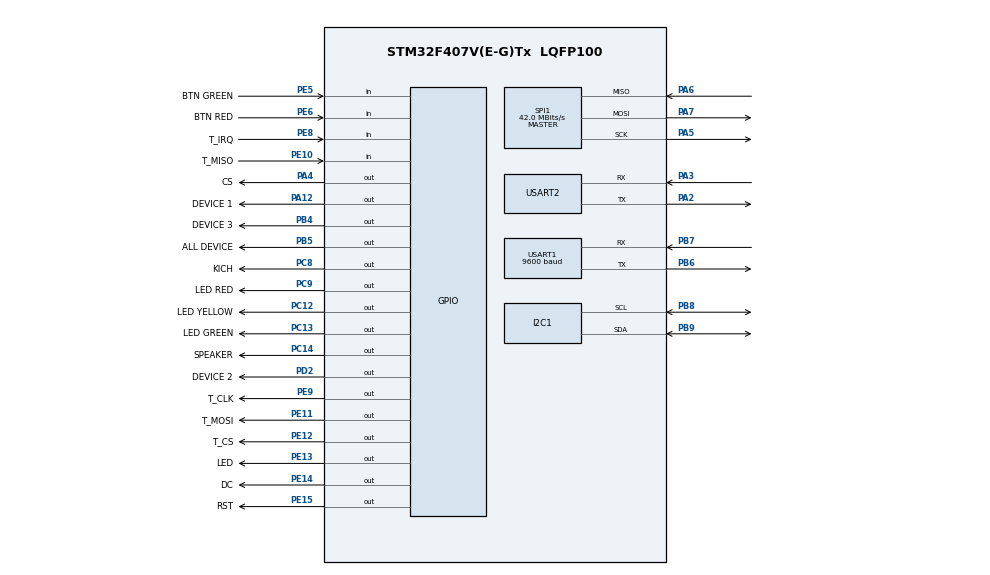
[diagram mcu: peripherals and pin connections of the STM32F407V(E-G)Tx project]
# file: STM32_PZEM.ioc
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Dma.Request0=USART1_RX
Dma.Request1=USART2_RX
Dma.Request2=USART2_TX
Dma.USART1_RX.0.Direction=DMA_PERIPH_TO_MEMORY
Dma.USART1_RX.0.FIFOMode=DMA_FIFOMODE_DISABLE
Dma.USART1_RX.0.Instance=DMA2_Stream2
Dma.USART1_RX.0.MemDataAlignment=DMA_MDATAALIGN_BYTE
Dma.USART1_RX.0.MemInc=DMA_MINC_ENABLE
Dma.USART1_RX.0.Mode=DMA_CIRCULAR
Dma.USART1_RX.0.PeriphDataAlignment=DMA_PDATAALIGN_BYTE
Dma.USART1_RX.0.PeriphInc=DMA_PINC_DISABLE
Dma.USART1_RX.0.Priority=DMA_PRIORITY_LOW
Dma.USART2_RX.1.Direction=DMA_PERIPH_TO_MEMORY
Dma.USART2_RX.1.FIFOMode=DMA_FIFOMODE_DISABLE
Dma.USART2_RX.1.Instance=DMA1_Stream5
Dma.USART2_RX.1.MemDataAlignment=DMA_MDATAALIGN_BYTE
Dma.USART2_RX.1.MemInc=DMA_MINC_ENABLE
Dma.USART2_RX.1.Mode=DMA_CIRCULAR
Dma.USART2_RX.1.PeriphDataAlignment=DMA_PDATAALIGN_BYTE
Dma.USART2_RX.1.PeriphInc=DMA_PINC_DISABLE
Dma.USART2_RX.1.Priority=DMA_PRIORITY_LOW
Dma.USART2_TX.2.Direction=DMA_MEMORY_TO_PERIPH
Dma.USART2_TX.2.FIFOMode=DMA_FIFOMODE_DISABLE
Dma.USART2_TX.2.Instance=DMA1_Stream6
Dma.USART2_TX.2.MemDataAlignment=DMA_MDATAALIGN_BYTE
Dma.USART2_TX.2.MemInc=DMA_MINC_ENABLE
Dma.USART2_TX.2.Mode=DMA_CIRCULAR
Dma.USART2_TX.2.PeriphDataAlignment=DMA_PDATAALIGN_BYTE
Dma.USART2_TX.2.PeriphInc=DMA_PINC_DISABLE
Dma.USART2_TX.2.Priority=DMA_PRIORITY_LOW
FREERTOS.Tasks01=Task_TFT,40,256,Start_Task_TFT,Default,NULL,Dynamic,NULL,NULL;Task_TOUCH,40,128,Start_Task_TOUCH,Default,NULL,Dynamic,NULL,NULL;Task_PZEM,39,128,Start_Task_PZEM,Default,NULL,Dynamic,NULL,NULL;Task_ESP32,39,128,Start_Task_ESP32,Default,NULL,Dynamic,NULL,NULL;Task_DS3231,39,128,Start_Task_DS3231,Default,NULL,Dynamic,NULL,NULL;Task_RUN,39,256,Start_Task_RUN,Default,NULL,Dynamic,NULL,NULL
Mcu.Family=STM32F4
Mcu.Name=STM32F407V(E-G)Tx
Mcu.Package=LQFP100
NVIC.DMA1_Stream5_IRQn=true\:5\:0\:false\:false\:true\:true\:false\:true
NVIC.DMA1_Stream6_IRQn=true\:5\:0\:false\:false\:true\:true\:false\:true
NVIC.DMA2_Stream2_IRQn=true\:5\:0\:false\:false\:true\:true\:false\:true
NVIC.I2C1_EV_IRQn=true\:5\:0\:false\:false\:true\:false\:true\:true
NVIC.PriorityGroup=NVIC_PRIORITYGROUP_4
NVIC.SPI1_IRQn=true\:5\:0\:false\:false\:true\:false\:true\:true
NVIC.TIM1_UP_TIM10_IRQn=true\:0\:0\:false\:false\:true\:false\:false\:true
NVIC.TIM7_IRQn=true\:5\:0\:false\:false\:true\:false\:true\:true
NVIC.TimeBase=TIM1_UP_TIM10_IRQn
NVIC.TimeBaseIP=TIM1
NVIC.USART1_IRQn=true\:5\:0\:false\:false\:true\:false\:true\:true
NVIC.USART2_IRQn=true\:5\:0\:false\:false\:true\:true\:true\:true
PA12.GPIO_Label=DEVICE 1
PA12.GPIO_Speed=GPIO_SPEED_FREQ_VERY_HIGH
PA12.Signal=GPIO_Output
PA13.Mode=Serial_Wire
PA13.Signal=SYS_JTMS-SWDIO
PA14.Mode=Serial_Wire
PA14.Signal=SYS_JTCK-SWCLK
PA2.GPIO_ModeDefaultPP=GPIO_MODE_AF_PP
PA2.GPIO_PuPd=GPIO_NOPULL
PA2.GPIO_Speed=GPIO_SPEED_FREQ_VERY_HIGH
PA2.Mode=Asynchronous
PA2.Signal=USART2_TX
PA3.GPIO_ModeDefaultPP=GPIO_MODE_AF_PP
PA3.GPIO_PuPd=GPIO_NOPULL
PA3.GPIO_Speed=GPIO_SPEED_FREQ_VERY_HIGH
PA3.Mode=Asynchronous
PA3.Signal=USART2_RX
PA4.GPIO_Label=CS
PA4.GPIO_PuPd=GPIO_NOPULL
PA4.GPIO_Speed=GPIO_SPEED_FREQ_VERY_HIGH
PA4.Signal=GPIO_Output
PA5.Mode=Full_Duplex_Master
PA5.Signal=SPI1_SCK
PA6.Mode=Full_Duplex_Master
PA6.Signal=SPI1_MISO
PA7.Mode=Full_Duplex_Master
PA7.Signal=SPI1_MOSI
PB4.GPIO_Label=DEVICE 3
PB4.GPIO_Speed=GPIO_SPEED_FREQ_VERY_HIGH
PB4.Signal=GPIO_Output
PB5.GPIO_Label=ALL DEVICE
PB5.GPIO_Speed=GPIO_SPEED_FREQ_VERY_HIGH
PB5.Signal=GPIO_Output
PB6.GPIO_ModeDefaultPP=GPIO_MODE_AF_PP
PB6.GPIO_PuPd=GPIO_NOPULL
PB6.GPIO_Speed=GPIO_SPEED_FREQ_VERY_HIGH
PB6.Mode=Asynchronous
PB6.Signal=USART1_TX
PB7.GPIO_ModeDefaultPP=GPIO_MODE_AF_PP
PB7.GPIO_PuPd=GPIO_NOPULL
PB7.GPIO_Speed=GPIO_SPEED_FREQ_VERY_HIGH
PB7.Mode=Asynchronous
PB7.Signal=USART1_RX
PB8.Mode=I2C
PB8.Signal=I2C1_SCL
PB9.Mode=I2C
PB9.Signal=I2C1_SDA
PC12.GPIO_Label=LED YELLOW
PC12.GPIO_ModeDefaultOutputPP=GPIO_MODE_OUTPUT_PP
PC12.GPIO_PuPd=GPIO_NOPULL
PC12.GPIO_Speed=GPIO_SPEED_FREQ_VERY_HIGH
PC12.PinState=GPIO_PIN_RESET
PC12.Signal=GPIO_Output
PC13-ANTI_TAMP.GPIO_Label=LED GREEN
PC13-ANTI_TAMP.GPIO_ModeDefaultOutputPP=GPIO_MODE_OUTPUT_PP
PC13-ANTI_TAMP.GPIO_PuPd=GPIO_NOPULL
PC13-ANTI_TAMP.GPIO_Speed=GPIO_SPEED_FREQ_LOW
PC13-ANTI_TAMP.PinState=GPIO_PIN_RESET
PC13-ANTI_TAMP.Signal=GPIO_Output
PC14-OSC32_IN.GPIO_Label=SPEAKER
PC14-OSC32_IN.Signal=GPIO_Output
PC8.GPIO_Label=KICH
PC8.GPIO_ModeDefaultOutputPP=GPIO_MODE_OUTPUT_PP
PC8.GPIO_PuPd=GPIO_NOPULL
PC8.GPIO_Speed=GPIO_SPEED_FREQ_VERY_HIGH
PC8.PinState=GPIO_PIN_SET
PC8.Signal=GPIO_Output
PC9.GPIO_Label=LED RED
PC9.GPIO_ModeDefaultOutputPP=GPIO_MODE_OUTPUT_PP
PC9.GPIO_PuPd=GPIO_NOPULL
PC9.GPIO_Speed=GPIO_SPEED_FREQ_VERY_HIGH
PC9.PinState=GPIO_PIN_RESET
PC9.Signal=GPIO_Output
PD2.GPIO_Label=DEVICE 2
PD2.GPIO_Speed=GPIO_SPEED_FREQ_VERY_HIGH
PD2.Signal=GPIO_Output
PE10.GPIO_Label=T_MISO
PE10.GPIO_PuPd=GPIO_PULLUP
PE10.Signal=GPIO_Input
PE11.GPIO_Label=T_MOSI
PE11.GPIO_PuPd=GPIO_NOPULL
PE11.GPIO_Speed=GPIO_SPEED_FREQ_VERY_HIGH
PE11.Signal=GPIO_Output
PE12.GPIO_Label=T_CS
PE12.GPIO_PuPd=GPIO_NOPULL
PE12.GPIO_Speed=GPIO_SPEED_FREQ_VERY_HIGH
PE12.Signal=GPIO_Output
PE13.GPIO_Label=LED
PE13.GPIO_PuPd=GPIO_NOPULL
PE13.GPIO_Speed=GPIO_SPEED_FREQ_VERY_HIGH
PE13.PinState=GPIO_PIN_SET
PE13.Signal=GPIO_Output
PE14.GPIO_Label=DC
PE14.GPIO_PuPd=GPIO_NOPULL
PE14.GPIO_Speed=GPIO_SPEED_FREQ_VERY_HIGH
PE14.Signal=GPIO_Output
PE15.GPIO_Label=RST
PE15.GPIO_PuPd=GPIO_NOPULL
PE15.GPIO_Speed=GPIO_SPEED_FREQ_VERY_HIGH
PE15.Signal=GPIO_Output
PE5.GPIO_Label=BTN GREEN
PE5.GPIO_PuPd=GPIO_PULLUP
PE5.Signal=GPIO_Input
PE6.GPIO_Label=BTN RED
PE6.GPIO_PuPd=GPIO_PULLUP
PE6.Signal=GPIO_Input
PE8.GPIO_Label=T_IRQ
PE8.GPIO_PuPd=GPIO_NOPULL
PE8.Signal=GPIO_Input
PE9.GPIO_Label=T_CLK
PE9.GPIO_PuPd=GPIO_NOPULL
PE9.GPIO_Speed=GPIO_SPEED_FREQ_VERY_HIGH
PE9.Signal=GPIO_Output
PH0-OSC_IN.Mode=HSE-External-Oscillator
PH0-OSC_IN.Signal=RCC_OSC_IN
PH1-OSC_OUT.Mode=HSE-External-Oscillator
PH1-OSC_OUT.Signal=RCC_OSC_OUT
ProjectManager.HeapSize=0x200
ProjectManager.StackSize=0x400
ProjectManager.TargetToolchain=EWARM V8.32
RCC.48MHZClocksFreq_Value=84000000
RCC.AHBFreq_Value=168000000
RCC.APB1CLKDivider=RCC_HCLK_DIV4
RCC.APB1Freq_Value=42000000
RCC.APB1TimFreq_Value=84000000
RCC.APB2CLKDivider=RCC_HCLK_DIV2
RCC.APB2Freq_Value=84000000
RCC.APB2TimFreq_Value=168000000
RCC.CortexFreq_Value=168000000
RCC.HCLKFreq_Value=168000000
RCC.HSE_VALUE=8000000
RCC.HSI_VALUE=16000000
RCC.LSE_VALUE=32768
RCC.PLLM=8
RCC.PLLN=336
RCC.PLLSourceVirtual=RCC_PLLSOURCE_HSE
RCC.SYSCLKFreq_VALUE=168000000
RCC.SYSCLKSource=RCC_SYSCLKSOURCE_PLLCLK
RCC.VCOOutputFreq_Value=336000000
SPI1.CalculateBaudRate=42.0 MBits/s
SPI1.Direction=SPI_DIRECTION_2LINES
SPI1.Mode=SPI_MODE_MASTER
SPI1.VirtualType=VM_MASTER
TIM6.AutoReloadPreload=TIM_AUTORELOAD_PRELOAD_ENABLE
TIM6.Prescaler=0
TIM7.AutoReloadPreload=TIM_AUTORELOAD_PRELOAD_DISABLE
TIM7.Period=9999
TIM7.Prescaler=84
USART1.BaudRate=9600
USART1.VirtualMode=VM_ASYNC
USART2.VirtualMode=VM_ASYNC
VP_FREERTOS_VS_CMSIS_V2.Mode=CMSIS_V2
VP_SYS_VS_tim1.Mode=TIM1
VP_TIM6_VS_ClockSourceINT.Mode=Enable_Timer
VP_TIM7_VS_ClockSourceINT.Mode=Enable_Timer
board=custom

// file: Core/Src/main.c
/* USER CODE BEGIN Header */
/**
  ******************************************************************************
  * @file           : main.c
  * @brief          : Main program body
  ******************************************************************************
  * @attention
  *
  * <h2><center>&copy; Copyright (c) 2020 STMicroelectronics.
  * All rights reserved.</center></h2>
  *
  * This software component is licensed by ST under BSD 3-Clause license,
  * the "License"; You may not use this file except in compliance with the
  * License. You may obtain a copy of the License at:
  *                        opensource.org/licenses/BSD-3-Clause
  *
  ******************************************************************************
  */
/* USER CODE END Header */
#include "main.h"
#include "cmsis_os.h"
#include "dma.h"
#include "i2c.h"
#include "spi.h"
#include "tim.h"
#include "usart.h"
#include "gpio.h"

/* USER CODE BEGIN Includes */
#include "math.h"
#include "ILI9341_Touchscreen.h"
#include "ILI9341_STM32_Driver.h"
#include "ILI9341_GFX.h"
#include "5x5_font.h"
#include "DS3231_H.h"
#include "stdbool.h"
/* USER CODE END Includes */

/* USER CODE BEGIN PTD */
//control device
#define D1_on    HAL_GPIO_WritePin(GPIOA,GPIO_PIN_12,GPIO_PIN_SET)
#define D1_off   HAL_GPIO_WritePin(GPIOA,GPIO_PIN_12,GPIO_PIN_RESET)
#define D2_on    HAL_GPIO_WritePin(GPIOD,GPIO_PIN_2,GPIO_PIN_SET)
#define D2_off   HAL_GPIO_WritePin(GPIOD,GPIO_PIN_2,GPIO_PIN_RESET)
#define D3_on    HAL_GPIO_WritePin(GPIOB,GPIO_PIN_4,GPIO_PIN_SET)
#define D3_off   HAL_GPIO_WritePin(GPIOB,GPIO_PIN_4,GPIO_PIN_RESET)
#define DALL_on  HAL_GPIO_WritePin(GPIOB,GPIO_PIN_5,GPIO_PIN_SET)
#define DALL_off HAL_GPIO_WritePin(GPIOB,GPIO_PIN_5,GPIO_PIN_RESET)
//control led and speaker
#define LEDG_on    HAL_GPIO_WritePin(GPIOC,GPIO_PIN_13,GPIO_PIN_RESET)
#define LEDG_off   HAL_GPIO_WritePin(GPIOC,GPIO_PIN_13,GPIO_PIN_SET)
#define LEDY_on    HAL_GPIO_WritePin(GPIOC,GPIO_PIN_12,GPIO_PIN_RESET)
#define LEDY_off   HAL_GPIO_WritePin(GPIOC,GPIO_PIN_12,GPIO_PIN_SET)
#define LEDR_on    HAL_GPIO_WritePin(GPIOC,GPIO_PIN_9,GPIO_PIN_RESET)
#define LEDR_off   HAL_GPIO_WritePin(GPIOC,GPIO_PIN_9,GPIO_PIN_SET)
#define SPK_on     HAL_GPIO_WritePin(GPIOC,GPIO_PIN_14,GPIO_PIN_RESET)
#define SPK_off    HAL_GPIO_WritePin(GPIOC,GPIO_PIN_14,GPIO_PIN_SET)
#define KICH_on     HAL_GPIO_WritePin(GPIOC,GPIO_PIN_8,GPIO_PIN_RESET)
#define KICH_off    HAL_GPIO_WritePin(GPIOC,GPIO_PIN_8,GPIO_PIN_SET)
//read button
#define BTNR        HAL_GPIO_ReadPin(GPIOE,GPIO_PIN_5)
#define BTNG        HAL_GPIO_ReadPin(GPIOE,GPIO_PIN_6)
/* USER CODE END PTD */

/* USER CODE BEGIN PV */
extern uint8_t btn[2];
 uint8_t control=0;
extern uint8_t touch;
extern bool status;
extern uint8_t t;
/* USER CODE END PV */

void SystemClock_Config(void);
void MX_FREERTOS_Init(void);

/* USER CODE BEGIN 0 */
void delay_us(uint16_t au16_us)
{
    htim6.Instance->CNT = 0;
    while (htim6.Instance->CNT < au16_us);
}

void delay_ms(uint16_t au16_ms)
{
    while(au16_ms > 0)
    {
	htim6.Instance->CNT = 0;
	au16_ms--;
	while (htim6.Instance->CNT < 1000);
    }
}
/* USER CODE END 0 */

int main(void)
{

  /* MCU Configuration--------------------------------------------------------*/

  /* Reset of all peripherals, Initializes the Flash interface and the Systick. */
  HAL_Init();

  /* Configure the system clock */
  SystemClock_Config();

  /* Initialize all configured peripherals */
  MX_GPIO_Init();
  MX_DMA_Init();
  MX_USART1_UART_Init();
  MX_I2C1_Init();
  MX_SPI1_Init();
  MX_TIM6_Init();
  MX_TIM7_Init();
  MX_USART2_UART_Init();
  /* USER CODE BEGIN 2 */
  HAL_TIM_Base_Start_IT(&htim7);
 // HAL_UART_Receive_DMA(&huart2,(uint8_t *)ESP32_recei,7);
  ILI9341_Init();
  ILI9341_Fill_Screen(BLACK);
  ILI9341_Set_Rotation(SCREEN_HORIZONTAL_2);
  ILI9341_Draw_Text("SYSTEM ENERGY", 15, 100, BLUE, 3, BLACK);
  ILI9341_Draw_Text("KTMT-K18", 30, 140, GREEN, 3, BLACK);
  ILI9341_Draw_Text("Please wait..........", 15, 200, CYAN, 2, BLACK);
  HAL_Delay(1000);
  ILI9341_Fill_Screen(BLACK);
  touch=1;
  control=1;
  /* USER CODE END 2 */

  /* Init scheduler */
  osKernelInitialize();  /* Call init function for freertos objects (in freertos.c) */
  MX_FREERTOS_Init();
  /* Start scheduler */
  osKernelStart();

  /* We should never get here as control is now taken by the scheduler */
  /* Infinite loop */
  while (1)
  {

  }
}

void SystemClock_Config(void)
{
  RCC_OscInitTypeDef RCC_OscInitStruct = {0};
  RCC_ClkInitTypeDef RCC_ClkInitStruct = {0};

  /** Configure the main internal regulator output voltage
  */
  __HAL_RCC_PWR_CLK_ENABLE();
  __HAL_PWR_VOLTAGESCALING_CONFIG(PWR_REGULATOR_VOLTAGE_SCALE1);
  /** Initializes the RCC Oscillators according to the specified parameters
  * in the RCC_OscInitTypeDef structure.
  */
  RCC_OscInitStruct.OscillatorType = RCC_OSCILLATORTYPE_HSE;
  RCC_OscInitStruct.HSEState = RCC_HSE_ON;
  RCC_OscInitStruct.PLL.PLLState = RCC_PLL_ON;
  RCC_OscInitStruct.PLL.PLLSource = RCC_PLLSOURCE_HSE;
  RCC_OscInitStruct.PLL.PLLM = 4;
  RCC_OscInitStruct.PLL.PLLN = 64;
  RCC_OscInitStruct.PLL.PLLP = RCC_PLLP_DIV2;
  RCC_OscInitStruct.PLL.PLLQ = 2;
  if (HAL_RCC_OscConfig(&RCC_OscInitStruct) != HAL_OK)
  {
    Error_Handler();
  }
  /** Initializes the CPU, AHB and APB buses clocks
  */
  RCC_ClkInitStruct.ClockType = RCC_CLOCKTYPE_HCLK|RCC_CLOCKTYPE_SYSCLK
                              |RCC_CLOCKTYPE_PCLK1|RCC_CLOCKTYPE_PCLK2;
  RCC_ClkInitStruct.SYSCLKSource = RCC_SYSCLKSOURCE_PLLCLK;
  RCC_ClkInitStruct.AHBCLKDivider = RCC_SYSCLK_DIV1;
  RCC_ClkInitStruct.APB1CLKDivider = RCC_HCLK_DIV4;
  RCC_ClkInitStruct.APB2CLKDivider = RCC_HCLK_DIV2;

  if (HAL_RCC_ClockConfig(&RCC_ClkInitStruct, FLASH_LATENCY_5) != HAL_OK)
  {
    Error_Handler();
  }
}

void HAL_TIM_PeriodElapsedCallback(TIM_HandleTypeDef *htim)
{
  if (htim->Instance == TIM1) {
    HAL_IncTick();
  }
  /* USER CODE BEGIN Callback 1 */
  if(htim->Instance ==TIM7)
  {
    btn[0]=BTNR;
    btn[1]=BTNG;
    if(btn[1]==1)
    {
      delay_ms(200);
      do
      {
        btn[1]=BTNG;
      }
      while(btn[1]==1);
      delay_ms(200);
      t=0;
    }
    if(btn[0]==1)
    {
      delay_ms(200);
      do
      {
        btn[0]=BTNR;
      }
      while(btn[0]==1);
      delay_ms(200);
      status=false;
    }
  }
  /* USER CODE END Callback 1 */
}

void Error_Handler(void)
{
}

/************************ (C) COPYRIGHT STMicroelectronics *****END OF FILE****/

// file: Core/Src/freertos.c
/* USER CODE BEGIN Header */
/**
  ******************************************************************************
  * File Name          : freertos.c
  * Description        : Code for freertos applications
  ******************************************************************************
  * @attention
  *
  * <h2><center>&copy; Copyright (c) 2020 STMicroelectronics.
  * All rights reserved.</center></h2>
  *
  * This software component is licensed by ST under Ultimate Liberty license
  * SLA0044, the "License"; You may not use this file except in compliance with
  * the License. You may obtain a copy of the License at:
  *                             www.st.com/SLA0044
  *
  ******************************************************************************
  */
/* USER CODE END Header */

#include "FreeRTOS.h"
#include "task.h"
#include "main.h"
#include "cmsis_os.h"

/* USER CODE BEGIN Includes */
//control device
#define D1_on    HAL_GPIO_WritePin(GPIOA,GPIO_PIN_12,GPIO_PIN_SET)
#define D1_off   HAL_GPIO_WritePin(GPIOA,GPIO_PIN_12,GPIO_PIN_RESET)
#define D2_on    HAL_GPIO_WritePin(GPIOD,GPIO_PIN_2,GPIO_PIN_SET)
#define D2_off   HAL_GPIO_WritePin(GPIOD,GPIO_PIN_2,GPIO_PIN_RESET)
#define D3_on    HAL_GPIO_WritePin(GPIOB,GPIO_PIN_4,GPIO_PIN_SET)
#define D3_off   HAL_GPIO_WritePin(GPIOB,GPIO_PIN_4,GPIO_PIN_RESET)
#define DALL_on  HAL_GPIO_WritePin(GPIOB,GPIO_PIN_5,GPIO_PIN_SET)
#define DALL_off HAL_GPIO_WritePin(GPIOB,GPIO_PIN_5,GPIO_PIN_RESET)
//control led and speaker
#define LEDG_on    HAL_GPIO_WritePin(GPIOC,GPIO_PIN_13,GPIO_PIN_RESET)
#define LEDG_off   HAL_GPIO_WritePin(GPIOC,GPIO_PIN_13,GPIO_PIN_SET)
#define LEDY_on    HAL_GPIO_WritePin(GPIOC,GPIO_PIN_12,GPIO_PIN_RESET)
#define LEDY_off   HAL_GPIO_WritePin(GPIOC,GPIO_PIN_12,GPIO_PIN_SET)
#define LEDR_on    HAL_GPIO_WritePin(GPIOC,GPIO_PIN_9,GPIO_PIN_RESET)
#define LEDR_off   HAL_GPIO_WritePin(GPIOC,GPIO_PIN_9,GPIO_PIN_SET)
#define SPK_on     HAL_GPIO_WritePin(GPIOC,GPIO_PIN_14,GPIO_PIN_RESET)
#define SPK_off    HAL_GPIO_WritePin(GPIOC,GPIO_PIN_14,GPIO_PIN_SET)
#define KICH_on     HAL_GPIO_WritePin(GPIOC,GPIO_PIN_8,GPIO_PIN_RESET)
#define KICH_off    HAL_GPIO_WritePin(GPIOC,GPIO_PIN_8,GPIO_PIN_SET)
//read button
#define BTNR        HAL_GPIO_ReadPin(GPIOE,GPIO_PIN_6)
#define BTNG        HAL_GPIO_ReadPin(GPIOE,GPIO_PIN_5)
//library
#include "math.h"
#include "ILI9341_Touchscreen.h"
#include "ILI9341_STM32_Driver.h"
#include "ILI9341_GFX.h"
#include "5x5_font.h"
#include "DS3231_H.h"
#include "string.h"
#include "stdio.h"
#include "stdint.h"
#include "stdbool.h"
/* USER CODE END Includes */

/* USER CODE BEGIN PTD */
//PZEM
uint8_t pzem_cmd[8] = {0xf8, 0x04, 0x00, 0x00, 0x00, 0x0A, 0x64, 0x64};//pzem cmd
//uint8_t pzem_cmd[4] = {0xf8, 0x42,0x41, 0xC2};//
//uint8_t pzem_cmd[6] = {0xF8,0x41,0x37,0x21,0x78,0xB7};
uint8_t data[25];//data pzem
uint16_t int_volt,dec_volt,int_freq,dec_freq,dec_current,int_current,dec_power,int_power,dec_energy,int_energy;//data display
//button
uint8_t btn[2];
extern uint8_t control;
//uart ESP32
uint8_t ESP32_send[17],ESP32_recei[10];
//control tft
uint16_t x_pos,y_pos;
uint8_t touch=0,d0=0,d1=0,d2=0,d3=0,k;
uint8_t d[8];
int cnt=0;
uint32_t threshold=0;
char Buffer[40];
uint8_t t=0;
bool on1=false,on2=false,on3=false,on4=false,status,event_touch;
//control task
int task1,task2,task3,task4,task5,task6;
extern DS3231_t DS3231;
extern UART_HandleTypeDef huart1;
extern UART_HandleTypeDef huart2;
/* USER CODE END PTD */

/* USER CODE BEGIN PM */
typedef struct {
  uint16_t volt;
  uint32_t current;
  uint16_t freq;
  uint32_t energy;
  uint32_t power;
}PZEM_t;
PZEM_t PZEM;
/* USER CODE END PM */

/* Definitions for Task_TFT */
osThreadId_t Task_TFTHandle;
const osThreadAttr_t Task_TFT_attributes = {
  .name = "Task_TFT",
  .priority = (osPriority_t) osPriorityHigh,
  .stack_size = 256 * 4
};
/* Definitions for Task_TOUCH */
osThreadId_t Task_TOUCHHandle;
const osThreadAttr_t Task_TOUCH_attributes = {
  .name = "Task_TOUCH",
  .priority = (osPriority_t) osPriorityHigh,
  .stack_size = 128 * 4
};
/* Definitions for Task_PZEM */
osThreadId_t Task_PZEMHandle;
const osThreadAttr_t Task_PZEM_attributes = {
  .name = "Task_PZEM",
  .priority = (osPriority_t) osPriorityAboveNormal7,
  .stack_size = 128 * 4
};
/* Definitions for Task_ESP32 */
osThreadId_t Task_ESP32Handle;
const osThreadAttr_t Task_ESP32_attributes = {
  .name = "Task_ESP32",
  .priority = (osPriority_t) osPriorityAboveNormal7,
  .stack_size = 128 * 4
};
/* Definitions for Task_DS3231 */
osThreadId_t Task_DS3231Handle;
const osThreadAttr_t Task_DS3231_attributes = {
  .name = "Task_DS3231",
  .priority = (osPriority_t) osPriorityAboveNormal7,
  .stack_size = 128 * 4
};
/* Definitions for Task_RUN */
osThreadId_t Task_RUNHandle;
const osThreadAttr_t Task_RUN_attributes = {
  .name = "Task_RUN",
  .priority = (osPriority_t) osPriorityAboveNormal7,
  .stack_size = 256 * 4
};

void Start_Task_TFT(void *argument);
void Start_Task_TOUCH(void *argument);
void Start_Task_PZEM(void *argument);
void Start_Task_ESP32(void *argument);
void Start_Task_DS3231(void *argument);
void Start_Task_RUN(void *argument);

void MX_FREERTOS_Init(void); /* (MISRA C 2004 rule 8.1) */

void MX_FREERTOS_Init(void) {
  /* USER CODE BEGIN Init */
  LEDR_on;
  LEDG_on;
  LEDY_off;
  SPK_off;
  DALL_off;
  D1_off;
  D2_off;
  D3_off;
  /* USER CODE END Init */

  /* Create the thread(s) */
  /* creation of Task_TFT */
  Task_TFTHandle = osThreadNew(Start_Task_TFT, NULL, &Task_TFT_attributes);

  /* creation of Task_TOUCH */
  Task_TOUCHHandle = osThreadNew(Start_Task_TOUCH, NULL, &Task_TOUCH_attributes);

  /* creation of Task_PZEM */
  Task_PZEMHandle = osThreadNew(Start_Task_PZEM, NULL, &Task_PZEM_attributes);

  /* creation of Task_ESP32 */
  Task_ESP32Handle = osThreadNew(Start_Task_ESP32, NULL, &Task_ESP32_attributes);

  /* creation of Task_DS3231 */
  Task_DS3231Handle = osThreadNew(Start_Task_DS3231, NULL, &Task_DS3231_attributes);

  /* creation of Task_RUN */
  Task_RUNHandle = osThreadNew(Start_Task_RUN, NULL, &Task_RUN_attributes);

}

void Start_Task_TFT(void *argument)
{
  /* USER CODE BEGIN Start_Task_TFT */
  /* Infinite loop */
  for(;;)
  {
    task1++;
    if(touch==0)//page 0
    {
      ILI9341_Set_Rotation(SCREEN_HORIZONTAL_2);
      ILI9341_Draw_Text("SYSTEM ENERGY", 15, 10, BLUE, 3, BLACK);
      //volt
      sprintf(Buffer,"VOLT: %0.2d.%dV",int_volt,dec_volt);
      ILI9341_Draw_Text(Buffer, 20, 40, MAGENTA, 3,BLACK);
      //current
      sprintf(Buffer,"CURR: %0.1d.%dA ",int_current,dec_current);
      ILI9341_Draw_Text(Buffer, 20, 60, RED, 3, BLACK);
      //freq
      sprintf(Buffer,"FREQ: %0.2d.%dHz ",int_freq,dec_freq);
      ILI9341_Draw_Text(Buffer, 20, 80, ORANGE, 3, BLACK);
      //energy
      sprintf(Buffer,"ENER: %dWh",PZEM.energy);
      ILI9341_Draw_Text(Buffer, 20, 100, GREEN, 3, BLACK);
      //power
      sprintf(Buffer,"POWER: %0.1d.%dW ",int_power,dec_power);
      ILI9341_Draw_Text(Buffer, 20, 120, CYAN, 3, BLACK);
      //time-date
      sprintf(Buffer, "TIME-%0.2d:%0.2d:%0.2d", DS3231.hour,DS3231.min,DS3231.sec);
      ILI9341_Draw_Text(Buffer, 20, 180, RED, 3, BLACK);
      sprintf(Buffer, "T%d-%02d-%02d-20%02d",DS3231.day,DS3231.date,DS3231.month,DS3231.year);
      ILI9341_Draw_Text(Buffer, 20, 200, PINK, 3, BLACK);

      ILI9341_Draw_Filled_TAMGIAC(290,100,50,GREEN);
    }
    else if(touch==1)
    {
      ILI9341_Fill_Screen(BLACK);
      touch=2;
    }
    else if(touch==2)//page 1
    {
      ILI9341_Set_Rotation(SCREEN_HORIZONTAL_2);
      ILI9341_Draw_Text("SYSTEM ENERGY", 15, 10, BLUE, 3, BLACK);
      ILI9341_Draw_Text("DEVICE CONTROL", 80, 40, GREEN, 2, BLACK);
      //name
      ILI9341_Draw_Text("ALL DEVICE", 40,  80, RED, 3, BLACK);
      ILI9341_Draw_Text("DEVICE1", 40, 120, RED, 3, BLACK);
      ILI9341_Draw_Text("DEVICE2", 40, 160, RED, 3, BLACK);
      ILI9341_Draw_Text("DEVICE3", 40, 200, RED, 3, BLACK);
      if(d0==1)//device all
      {
        ILI9341_Set_Rotation(SCREEN_HORIZONTAL_2);
        ILI9341_Draw_Text("ON ", 230,  80, YELLOW, 2, BLACK);
        on1=true;
        DALL_on;
      }
      else if(d0==2)
      {
        ILI9341_Set_Rotation(SCREEN_HORIZONTAL_2);
        ILI9341_Draw_Text("OFF", 230,  80, YELLOW, 2, BLACK);
        on1=false;
        DALL_off;
      }
      if(d1==3)//device 1
      {
        ILI9341_Set_Rotation(SCREEN_HORIZONTAL_2);
        ILI9341_Draw_Text("ON ", 190,  120,YELLOW, 2,BLACK);
        on2=true;
        D1_on;
      }
      else if(d1==4)
      {
        ILI9341_Set_Rotation(SCREEN_HORIZONTAL_2);
        ILI9341_Draw_Text("OFF", 190,  120, YELLOW, 2,BLACK);
        on2=false;
        D1_off;
      }
      if(d2==5)//device 2
      {
        ILI9341_Set_Rotation(SCREEN_HORIZONTAL_2);
        ILI9341_Draw_Text("ON ", 190,  160, YELLOW, 2,BLACK);
        on2=true;
        D2_on;
      }
      else if(d2==6)
      {
        ILI9341_Set_Rotation(SCREEN_HORIZONTAL_2);
        ILI9341_Draw_Text("OFF", 190,  160, YELLOW, 2, BLACK);
        on2=false;
        D2_off;
      }
      if(d3==5)//device 3
      {
        ILI9341_Set_Rotation(SCREEN_HORIZONTAL_2);
        ILI9341_Draw_Text("ON ", 190,  200, YELLOW, 2, BLACK);
        on3=true;
        D3_on;
      }
      else if(d3==6)
      {
        ILI9341_Set_Rotation(SCREEN_HORIZONTAL_2);
        ILI9341_Draw_Text("OFF", 190,  200, YELLOW, 2, BLACK);
        on3=false;
        D3_off;
      }
      ILI9341_Set_Rotation(SCREEN_HORIZONTAL_1);
      ILI9341_Draw_Filled_TAMGIAC(290,100,50,GREEN);
    }
    if(touch==3)
    {
      ILI9341_Fill_Screen(BLACK);
      touch=0;
    }
    //device all on with app
    if(control==1)
    {
      if(d[0]==49)d0=1;
      else if(d[0]==48)d0=2;

      if(d[1]==49)d1=3;
      else if(d[1]==48)d1=4;

      if(d[2]==49)d2=5;
      else if(d[2]==48)d2=6;

      if(d[3]==49)d3=5;
      else if(d[3]==48)d3=6;
    }
    osDelay(1);
    //osThreadSuspend(Task_TFTHandle);
  }
  /* USER CODE END Start_Task_TFT */
}

void Start_Task_TOUCH(void *argument)
{
  /* USER CODE BEGIN Start_Task_TOUCH */
  /* Infinite loop */
  for(;;)
  {
    task2++;
//    if(TP_Touchpad_Pressed())
//    {
//      uint16_t position_array[2];
//      if(TP_Read_Coordinates(position_array) == TOUCHPAD_DATA_OK)
//      {
//        x_pos = position_array[0];
//        y_pos = position_array[1];
//        event_touch=true;
//        if(touch==0)//page 0
//        {
//          if(x_pos<250&&x_pos>200&&y_pos<50&&y_pos>20)touch=1;//page 0 sang page 1
//        }
//        else if(touch==2)
//        {
//          if(x_pos<240&&x_pos>200&&y_pos<300&&y_pos>280)touch=3;//page 1 ve page 0
//          if(x_pos<220&&x_pos>180&&y_pos<265&&y_pos>140&&on1==false)d0=1;//device all
//          if(x_pos<220&&x_pos>180&&y_pos<265&&y_pos>140&&on1==true)d0=2;
//          if(x_pos<250&&x_pos>220&&y_pos<265&&y_pos>140&&on2==false)d1=3;//device 1
//          if(x_pos<250&&x_pos>220&&y_pos<265&&y_pos>140&&on2==true)d1=4;
//          if(x_pos<280&&x_pos>250&&y_pos<265&&y_pos>140&&on3==false)d2=5;//device 2
//          if(x_pos<280&&x_pos>250&&y_pos<265&&y_pos>140&&on3==true)d2=6;
//          //if(x_pos<240&&x_pos>200&&y_pos<265&&y_pos>140)touch=3;//device 3
//        }
//      }
//    }
    osDelay(1);
  }
  /* USER CODE END Start_Task_TOUCH */
}

void Start_Task_PZEM(void *argument)
{
  /* USER CODE BEGIN Start_Task_PZEM */
  /* Infinite loop */
  for(;;)
  {
    task3++;
    if(status==true)HAL_GPIO_TogglePin(GPIOC,GPIO_PIN_12);

    HAL_UART_Transmit_IT(&huart1,(uint8_t *)pzem_cmd,8);//send_cmd den pzem
    HAL_UART_Receive_DMA(&huart1,(uint8_t *)data,25);//receive data tu pzem

    PZEM.volt=(data[3]<<8)+data[4];  //volt
    PZEM.current=(data[7]<<24)+(data[8]<<16)+(data[5]<<8)+(data[6]);//current
    PZEM.freq=(data[17]<<8)+data[18];//freq
    PZEM.energy=(data[15]<<24)+(data[16]<<16)+(data[13]<<8)+(data[14]);//energy
    PZEM.power=(data[11]<<24)+(data[12]<<16)+(data[9]<<8)+(data[10]);//power

    dec_volt=PZEM.volt%10;
    int_volt=PZEM.volt/10;

    dec_freq=PZEM.freq%10;
    int_freq=PZEM.freq/10;

    int_current=PZEM.current/1000;
    dec_current=PZEM.current%1000;

    dec_power=PZEM.power%10;
    int_power=PZEM.power/10;

    dec_energy=PZEM.energy%1000;
    int_energy=PZEM.energy/1000;

    osDelay(1);
    //osThreadSuspend(Task_PZEMHandle);
  }
  /* USER CODE END Start_Task_PZEM */
}

void Start_Task_ESP32(void *argument)
{
  /* USER CODE BEGIN Start_Task_ESP32 */
  /* Infinite loop */
  for(;;)
  {
    task4++;
    ESP32_send[0]=0xFF;//checksum

    ESP32_send[1]=data[3];
    ESP32_send[2]=data[4];//volt

    ESP32_send[3]=data[17];
    ESP32_send[4]=data[18];//freq

    ESP32_send[5]=data[7];
    ESP32_send[6]=data[8];//current
    ESP32_send[7]=data[5];
    ESP32_send[8]=data[6];

    ESP32_send[9]=data[15];
    ESP32_send[10]=data[16];//energy
    ESP32_send[11]=data[13];
    ESP32_send[12]=data[14];

    ESP32_send[13]=data[11];
    ESP32_send[14]=data[12];//power
    ESP32_send[15]=data[9];
    ESP32_send[16]=data[10];

    HAL_UART_Transmit_DMA(&huart2,(uint8_t *)ESP32_send,17);
    HAL_UART_Receive_DMA(&huart2,(uint8_t *)&ESP32_recei,10);

    if(ESP32_recei[0]==70&&ESP32_recei[9]==69)
    {
      d[0]=ESP32_recei[1]; // all device
      d[1]=ESP32_recei[2]; //device 1
      d[2]=ESP32_recei[3];//device 2
      d[3]=ESP32_recei[4];//device 3
      d[4]=ESP32_recei[5]; //threshold
      d[5]=ESP32_recei[6]; //threshold
      d[6]=ESP32_recei[7]; //threshold
      d[7]=ESP32_recei[8]; //threshold
    }
    threshold=(((d[4]-48)*1000)+((d[5]-48)*100)+((d[6]-48)*10)+(d[7]-48));

      if(t==0){
        if(int_power>threshold) //so sanh power voi nguong
        {
          status=true;
          t=1;
        }
      }
      if(t==1){
        if(status==true)
        {
          SPK_on;
          LEDG_off;
        }
        else{
          SPK_off;
          LEDG_on;
        }
      }

    osDelay(1);

  }
  /* USER CODE END Start_Task_ESP32 */
}

void Start_Task_DS3231(void *argument)
{
  /* USER CODE BEGIN Start_Task_DS3231 */
  /* Infinite loop */
  for(;;)
  {
    //task5++;
    GetTime();
    osDelay(10);
  }
  /* USER CODE END Start_Task_DS3231 */
}

void Start_Task_RUN(void *argument)
{
  /* USER CODE BEGIN Start_Task_RUN */
  /* Infinite loop */
  for(;;)
  {
    LEDY_on;
    delay_ms(5);
    LEDY_off;

    osDelay(1);
  }
  /* USER CODE END Start_Task_RUN */
}

/************************ (C) COPYRIGHT STMicroelectronics *****END OF FILE****/
